VERSION 5.6 ;

BUSBITCHARS "[]" ;

DIVIDERCHAR "/" ;

UNITS
    DATABASE MICRONS 2000 ;
END UNITS

MANUFACTURINGGRID 0.000500 ; 

CLEARANCEMEASURE EUCLIDEAN ; 

USEMINSPACING OBS ON ; 

SITE CoreSite
    CLASS CORE ;
    SIZE 2.400000 BY 2.400000 ;
END CoreSite

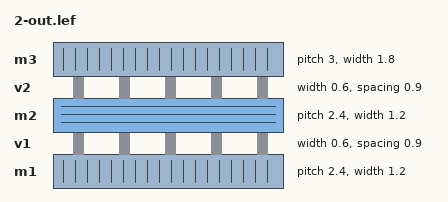
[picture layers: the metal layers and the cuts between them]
LAYER m1
   TYPE ROUTING ;
   DIRECTION VERTICAL ;
   MINWIDTH 1.200000 ;
   AREA 0.810000 ;
   WIDTH 1.200000 ;
   SPACINGTABLE
      PARALLELRUNLENGTH 0.0
      WIDTH 0.0 1.200000 ;
   PITCH 2.400000 2.400000 ;
END m1

LAYER v1
    TYPE CUT ;
    SPACING 0.900000 ;
    WIDTH 0.600000 ;
    ENCLOSURE ABOVE 0.300000 0.300000 ;
    ENCLOSURE BELOW 0.300000 0.300000 ;
END v1

LAYER m2
   TYPE ROUTING ;
   DIRECTION HORIZONTAL ;
   MINWIDTH 1.200000 ;
   AREA 0.810000 ;
   WIDTH 1.200000 ;
   SPACINGTABLE
      PARALLELRUNLENGTH 0.0
      WIDTH 0.0 1.200000 ;
   PITCH 2.400000 2.400000 ;
END m2

LAYER v2
    TYPE CUT ;
    SPACING 0.900000 ;
    WIDTH 0.600000 ;
    ENCLOSURE ABOVE 0.300000 0.300000 ;
    ENCLOSURE BELOW 0.300000 0.300000 ;
END v2

LAYER m3
   TYPE ROUTING ;
   DIRECTION VERTICAL ;
   MINWIDTH 1.800000 ;
   AREA 2.250000 ;
   WIDTH 1.800000 ;
   SPACINGTABLE
      PARALLELRUNLENGTH 0.0
      WIDTH 0.0 1.200000 ;
   PITCH 3.000000 3.000000 ;
END m3

LAYER OVERLAP
   TYPE OVERLAP ;
END OVERLAP

VIA v1_C DEFAULT
   LAYER m1 ;
     RECT -0.600000 -0.600000 0.600000 0.600000 ;
   LAYER v1 ;
     RECT -0.300000 -0.300000 0.300000 0.300000 ;
   LAYER m2 ;
     RECT -2.000000 -0.600000 2.000000 0.600000 ;
END v1_C

VIA v2_C DEFAULT
   LAYER m2 ;
     RECT -0.600000 -0.600000 0.600000 0.600000 ;
   LAYER v2 ;
     RECT -0.300000 -0.300000 0.300000 0.300000 ;
   LAYER m3 ;
     RECT -0.600000 -2.000000 0.600000 2.000000 ;
END v2_C

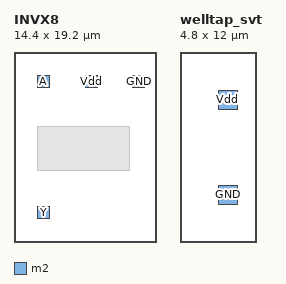
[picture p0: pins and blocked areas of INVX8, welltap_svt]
MACRO INVX8
    CLASS CORE ;
    FOREIGN INVX8 0.000000 0.000000 ;
    ORIGIN 0.000000 0.000000 ;
    SIZE 14.400000 BY 19.200000 ;
    SYMMETRY X Y ;
    SITE CoreSite ;
    PIN A
        DIRECTION INPUT ;
        USE SIGNAL ;
        PORT
        LAYER m2 ;
        RECT 2.400000 15.600000 3.600000 16.800000 ;
        END
    END A
    PIN Y
        DIRECTION OUTPUT ;
        USE SIGNAL ;
        PORT
        LAYER m2 ;
        RECT 2.400000 2.400000 3.600000 3.600000 ;
        END
        ANTENNADIFFAREA 36.000000 ;
    END Y
    PIN Vdd
        DIRECTION INPUT ;
        USE POWER ;
        PORT
        LAYER m2 ;
        RECT 7.200000 15.600000 8.400000 16.800000 ;
        END
        ANTENNADIFFAREA 28.800000 ;
    END Vdd
    PIN GND
        DIRECTION INPUT ;
        USE GROUND ;
        PORT
        LAYER m2 ;
        RECT 12.000000 15.600000 13.200000 16.800000 ;
        END
        ANTENNADIFFAREA 10.800000 ;
    END GND
    OBS
      LAYER m1 ;
         RECT 2.400000 7.200000 11.700000 11.700000 ;
    END
END INVX8

MACRO welltap_svt
    CLASS CORE WELLTAP ;
    FOREIGN welltap_svt 0.000000 0.000000 ;
    ORIGIN 0.000000 0.000000 ;
    SIZE 4.800000 BY 12.000000 ;
    SYMMETRY X Y ;
    SITE CoreSite ;
    PIN Vdd
        DIRECTION INPUT ;
        USE POWER ;
        PORT
        LAYER m2 ;
        RECT 2.400000 8.400000 3.600000 9.600000 ;
        END
    END Vdd
    PIN GND
        DIRECTION INPUT ;
        USE GROUND ;
        PORT
        LAYER m2 ;
        RECT 2.400000 2.400000 3.600000 3.600000 ;
        END
    END GND
END welltap_svt

